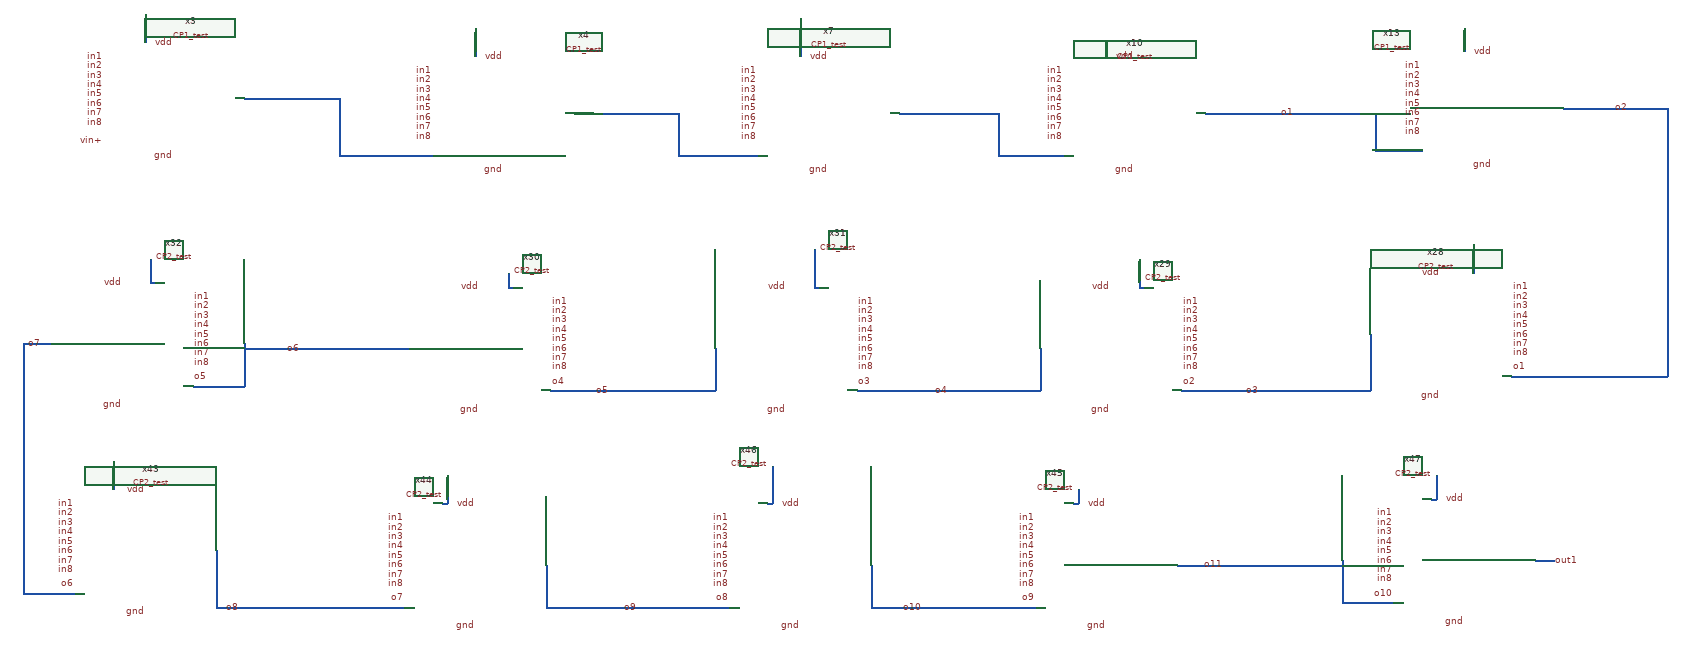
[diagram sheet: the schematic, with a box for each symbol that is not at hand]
v {xschem version=3.4.4 file_version=1.2
}
G {}
K {}
V {}
S {}
E {}
N -1210 -770 -1170 -770 {
lab=#net21}
N -1420 -910 -1420 -890 {
lab=#net22}
N -510 -740 -470 -740 {
lab=#net23}
N -720 -880 -720 -860 {
lab=#net24}
N 180 -740 220 -740 {
lab=#net25}
N -30 -880 -30 -860 {
lab=#net22}
N 830 -740 870 -740 {
lab=o1}
N 620 -880 620 -860 {
lab=#net26}
N 1590 -750 1630 -750 {
lab=o2}
N 1380 -890 1380 -870 {
lab=#net27}
N -1170 -770 -1010 -770 {
lab=#net21}
N -1010 -770 -1010 -650 {
lab=#net21}
N -1010 -650 -810 -650 {
lab=#net21}
N -480 -740 -290 -740 {
lab=#net23}
N -290 -740 -290 -650 {
lab=#net23}
N -290 -650 -120 -650 {
lab=#net23}
N 220 -740 390 -740 {
lab=#net25}
N 390 -740 390 -650 {
lab=#net25}
N 390 -650 530 -650 {
lab=#net25}
N 870 -740 1180 -740 {
lab=o1}
N -1420 -950 -1420 -910 {
lab=#net22}
N -720 -920 -720 -870 {
lab=#net24}
N -30 -940 -30 -880 {
lab=#net22}
N 620 -890 620 -870 {
lab=#net26}
N 1380 -920 1380 -900 {
lab=#net27}
N 1380 -900 1380 -890 {
lab=#net27}
N 690 -390 690 -370 {
lab=#net30}
N 0 -390 0 -370 {
lab=#net32}
N -1660 -250 -1620 -250 {
lab=o7}
N -1410 -400 -1410 -380 {
lab=#net36}
N -1210 -250 -1210 -160 {
lab=o6}
N 690 -430 690 -380 {
lab=#net30}
N 0 -450 0 -390 {
lab=#net32}
N -650 -400 -650 -380 {
lab=#net35}
N -1410 -430 -1410 -410 {
lab=#net36}
N -1410 -410 -1410 -400 {
lab=#net36}
N 1400 -460 1400 -400 {
lab=#net29}
N 690 -370 700 -370 {
lab=#net30}
N 0 -370 10 -370 {
lab=#net32}
N -650 -380 -650 -370 {
lab=#net35}
N -650 -370 -640 -370 {
lab=#net35}
N -1410 -380 -1400 -380 {
lab=#net36}
N -1320 -160 -1210 -160 {
lab=o6}
N -1210 -240 -860 -240 {
lab=o6}
N -560 -150 -210 -150 {
lab=o5}
N -210 -240 -210 -150 {
lab=o5}
N 90 -150 480 -150 {
lab=o4}
N 480 -240 480 -150 {
lab=o4}
N 780 -150 1180 -150 {
lab=o3}
N 1180 -270 1180 -150 {
lab=o3}
N 1480 -180 1570 -180 {
lab=o2}
N -780 70 -780 90 {
lab=#net40}
N -90 70 -90 90 {
lab=#net42}
N 1530 210 1570 210 {
lab=out1}
N 1320 60 1320 80 {
lab=#net46}
N 1120 210 1120 300 {
lab=o11}
N -780 30 -780 80 {
lab=#net40}
N -90 10 -90 70 {
lab=#net42}
N 560 60 560 80 {
lab=#net45}
N 1320 30 1320 50 {
lab=#net46}
N 1320 50 1320 60 {
lab=#net46}
N -1490 0 -1490 60 {
lab=#net39}
N -790 90 -780 90 {
lab=#net40}
N -100 90 -90 90 {
lab=#net42}
N 560 80 560 90 {
lab=#net45}
N 550 90 560 90 {
lab=#net45}
N 1310 80 1320 80 {
lab=#net46}
N 1120 300 1230 300 {
lab=o11}
N 770 220 1120 220 {
lab=o11}
N 120 310 470 310 {
lab=o10}
N 120 220 120 310 {
lab=o10}
N -570 310 -180 310 {
lab=o9}
N -570 220 -570 310 {
lab=o9}
N -1270 310 -870 310 {
lab=o8}
N -1270 190 -1270 310 {
lab=o8}
N 1190 -660 1290 -660 {}
N 1190 -740 1190 -660 {}
N 1160 -740 1190 -740 {}
N 1570 -180 1810 -180 {}
N 1810 -750 1810 -180 {}
N 1630 -750 1810 -750 {}
N -1680 -250 -1660 -250 {}
N -1680 -250 -1680 280 {}
N -1680 280 -1570 280 {}
C {CP1_test.sym} -1360 -770 0 0 {name=x3}
C {devices/lab_pin.sym} -1360 -890 1 0 {name=p143 sig_type=std_logic lab=vdd}
C {devices/lab_pin.sym} -1510 -860 0 0 {name=p145 sig_type=std_logic lab=in1
value=0}
C {devices/lab_pin.sym} -1510 -840 0 0 {name=p146 sig_type=std_logic lab=in2
value=0}
C {devices/lab_pin.sym} -1510 -820 0 0 {name=p147 sig_type=std_logic lab=in3
value=0}
C {devices/lab_pin.sym} -1510 -800 0 0 {name=p148 sig_type=std_logic lab=in4
value=0}
C {devices/lab_pin.sym} -1510 -780 0 0 {name=p149 sig_type=std_logic lab=in5
value=0}
C {devices/lab_pin.sym} -1510 -760 0 0 {name=p150 sig_type=std_logic lab=in6
value=0}
C {devices/lab_pin.sym} -1510 -740 0 0 {name=p151 sig_type=std_logic lab=in7
value=0}
C {devices/lab_pin.sym} -1510 -720 0 0 {name=p152 sig_type=std_logic lab=in8
value=0}
C {devices/lab_pin.sym} -1510 -680 0 0 {name=p153 sig_type=std_logic lab=vin+}
C {devices/lab_pin.sym} -1360 -650 3 0 {name=p190 sig_type=std_logic lab=gnd}
C {CP1_test.sym} -660 -740 0 0 {name=x4}
C {devices/lab_pin.sym} -660 -860 1 0 {name=p157 sig_type=std_logic lab=vdd}
C {devices/lab_pin.sym} -810 -830 0 0 {name=p158 sig_type=std_logic lab=in1
value=0}
C {devices/lab_pin.sym} -810 -810 0 0 {name=p159 sig_type=std_logic lab=in2
value=0}
C {devices/lab_pin.sym} -810 -790 0 0 {name=p160 sig_type=std_logic lab=in3
value=0}
C {devices/lab_pin.sym} -810 -770 0 0 {name=p161 sig_type=std_logic lab=in4
value=0}
C {devices/lab_pin.sym} -810 -750 0 0 {name=p162 sig_type=std_logic lab=in5
value=0}
C {devices/lab_pin.sym} -810 -730 0 0 {name=p163 sig_type=std_logic lab=in6
value=0}
C {devices/lab_pin.sym} -810 -710 0 0 {name=p164 sig_type=std_logic lab=in7
value=0}
C {devices/lab_pin.sym} -810 -690 0 0 {name=p165 sig_type=std_logic lab=in8
value=0}
C {devices/lab_pin.sym} -660 -620 3 0 {name=p166 sig_type=std_logic lab=gnd}
C {CP1_test.sym} 30 -740 0 0 {name=x7}
C {devices/lab_pin.sym} 30 -860 1 0 {name=p172 sig_type=std_logic lab=vdd}
C {devices/lab_pin.sym} -120 -830 0 0 {name=p173 sig_type=std_logic lab=in1
value=0}
C {devices/lab_pin.sym} -120 -810 0 0 {name=p174 sig_type=std_logic lab=in2
value=0}
C {devices/lab_pin.sym} -120 -790 0 0 {name=p175 sig_type=std_logic lab=in3
value=0}
C {devices/lab_pin.sym} -120 -770 0 0 {name=p176 sig_type=std_logic lab=in4
value=0}
C {devices/lab_pin.sym} -120 -750 0 0 {name=p177 sig_type=std_logic lab=in5
value=0}
C {devices/lab_pin.sym} -120 -730 0 0 {name=p178 sig_type=std_logic lab=in6
value=0}
C {devices/lab_pin.sym} -120 -710 0 0 {name=p179 sig_type=std_logic lab=in7
value=0}
C {devices/lab_pin.sym} -120 -690 0 0 {name=p180 sig_type=std_logic lab=in8
value=0}
C {devices/lab_pin.sym} 30 -620 3 0 {name=p181 sig_type=std_logic lab=gnd}
C {CP1_test.sym} 680 -740 0 0 {name=x10}
C {devices/lab_pin.sym} 680 -860 1 0 {name=p186 sig_type=std_logic lab=vdd}
C {devices/lab_pin.sym} 530 -830 0 0 {name=p187 sig_type=std_logic lab=in1
value=0}
C {devices/lab_pin.sym} 530 -810 0 0 {name=p188 sig_type=std_logic lab=in2
value=0}
C {devices/lab_pin.sym} 530 -790 0 0 {name=p189 sig_type=std_logic lab=in3
value=0}
C {devices/lab_pin.sym} 530 -770 0 0 {name=p191 sig_type=std_logic lab=in4
value=0}
C {devices/lab_pin.sym} 530 -750 0 0 {name=p192 sig_type=std_logic lab=in5
value=0}
C {devices/lab_pin.sym} 530 -730 0 0 {name=p193 sig_type=std_logic lab=in6
value=0}
C {devices/lab_pin.sym} 530 -710 0 0 {name=p194 sig_type=std_logic lab=in7
value=0}
C {devices/lab_pin.sym} 530 -690 0 0 {name=p195 sig_type=std_logic lab=in8
value=0}
C {devices/lab_pin.sym} 680 -620 3 0 {name=p196 sig_type=std_logic lab=gnd}
C {CP1_test.sym} 1440 -750 0 0 {name=x13}
C {devices/lab_pin.sym} 1440 -870 1 0 {name=p201 sig_type=std_logic lab=vdd}
C {devices/lab_pin.sym} 1290 -840 0 0 {name=p202 sig_type=std_logic lab=in1
value=0}
C {devices/lab_pin.sym} 1290 -820 0 0 {name=p203 sig_type=std_logic lab=in2
value=0}
C {devices/lab_pin.sym} 1290 -800 0 0 {name=p204 sig_type=std_logic lab=in3
value=0}
C {devices/lab_pin.sym} 1290 -780 0 0 {name=p205 sig_type=std_logic lab=in4
value=0}
C {devices/lab_pin.sym} 1290 -760 0 0 {name=p206 sig_type=std_logic lab=in5
value=0}
C {devices/lab_pin.sym} 1290 -740 0 0 {name=p207 sig_type=std_logic lab=in6
value=0}
C {devices/lab_pin.sym} 1290 -720 0 0 {name=p208 sig_type=std_logic lab=in7
value=0}
C {devices/lab_pin.sym} 1290 -700 0 0 {name=p209 sig_type=std_logic lab=in8
value=0}
C {devices/lab_pin.sym} 1440 -630 3 0 {name=p210 sig_type=std_logic lab=gnd}
C {devices/lab_pin.sym} 1330 -400 3 1 {name=p216 sig_type=std_logic lab=vdd}
C {devices/lab_pin.sym} 1480 -370 0 1 {name=p218 sig_type=std_logic lab=in1
value=0}
C {devices/lab_pin.sym} 1480 -350 0 1 {name=p219 sig_type=std_logic lab=in2
value=0}
C {devices/lab_pin.sym} 1480 -330 0 1 {name=p220 sig_type=std_logic lab=in3
value=0}
C {devices/lab_pin.sym} 1480 -310 0 1 {name=p221 sig_type=std_logic lab=in4
value=0}
C {devices/lab_pin.sym} 1480 -290 0 1 {name=p222 sig_type=std_logic lab=in5
value=0}
C {devices/lab_pin.sym} 1480 -270 0 1 {name=p223 sig_type=std_logic lab=in6
value=0}
C {devices/lab_pin.sym} 1480 -250 0 1 {name=p224 sig_type=std_logic lab=in7
value=0}
C {devices/lab_pin.sym} 1480 -230 0 1 {name=p225 sig_type=std_logic lab=in8
value=0}
C {devices/lab_pin.sym} 1330 -140 1 1 {name=p227 sig_type=std_logic lab=gnd}
C {devices/lab_pin.sym} 630 -370 3 1 {name=p232 sig_type=std_logic lab=vdd}
C {devices/lab_pin.sym} 780 -340 0 1 {name=p233 sig_type=std_logic lab=in1
value=0}
C {devices/lab_pin.sym} 780 -320 0 1 {name=p234 sig_type=std_logic lab=in2
value=0}
C {devices/lab_pin.sym} 780 -300 0 1 {name=p235 sig_type=std_logic lab=in3
value=0}
C {devices/lab_pin.sym} 780 -280 0 1 {name=p236 sig_type=std_logic lab=in4
value=0}
C {devices/lab_pin.sym} 780 -260 0 1 {name=p237 sig_type=std_logic lab=in5
value=0}
C {devices/lab_pin.sym} 780 -240 0 1 {name=p238 sig_type=std_logic lab=in6
value=0}
C {devices/lab_pin.sym} 780 -220 0 1 {name=p239 sig_type=std_logic lab=in7
value=0}
C {devices/lab_pin.sym} 780 -200 0 1 {name=p240 sig_type=std_logic lab=in8
value=0}
C {devices/lab_pin.sym} 630 -110 1 1 {name=p241 sig_type=std_logic lab=gnd}
C {devices/lab_pin.sym} -60 -370 3 1 {name=p246 sig_type=std_logic lab=vdd}
C {devices/lab_pin.sym} 90 -340 0 1 {name=p247 sig_type=std_logic lab=in1
value=0}
C {devices/lab_pin.sym} 90 -320 0 1 {name=p248 sig_type=std_logic lab=in2
value=0}
C {devices/lab_pin.sym} 90 -300 0 1 {name=p249 sig_type=std_logic lab=in3
value=0}
C {devices/lab_pin.sym} 90 -280 0 1 {name=p250 sig_type=std_logic lab=in4
value=0}
C {devices/lab_pin.sym} 90 -260 0 1 {name=p251 sig_type=std_logic lab=in5
value=0}
C {devices/lab_pin.sym} 90 -240 0 1 {name=p252 sig_type=std_logic lab=in6
value=0}
C {devices/lab_pin.sym} 90 -220 0 1 {name=p253 sig_type=std_logic lab=in7
value=0}
C {devices/lab_pin.sym} 90 -200 0 1 {name=p254 sig_type=std_logic lab=in8
value=0}
C {devices/lab_pin.sym} -60 -110 1 1 {name=p255 sig_type=std_logic lab=gnd}
C {devices/lab_pin.sym} -710 -370 3 1 {name=p260 sig_type=std_logic lab=vdd}
C {devices/lab_pin.sym} -560 -340 0 1 {name=p261 sig_type=std_logic lab=in1
value=0}
C {devices/lab_pin.sym} -560 -320 0 1 {name=p262 sig_type=std_logic lab=in2
value=0}
C {devices/lab_pin.sym} -560 -300 0 1 {name=p263 sig_type=std_logic lab=in3
value=0}
C {devices/lab_pin.sym} -560 -280 0 1 {name=p264 sig_type=std_logic lab=in4
value=0}
C {devices/lab_pin.sym} -560 -260 0 1 {name=p265 sig_type=std_logic lab=in5
value=0}
C {devices/lab_pin.sym} -560 -240 0 1 {name=p266 sig_type=std_logic lab=in6
value=0}
C {devices/lab_pin.sym} -560 -220 0 1 {name=p267 sig_type=std_logic lab=in7
value=0}
C {devices/lab_pin.sym} -560 -200 0 1 {name=p268 sig_type=std_logic lab=in8
value=0}
C {devices/lab_pin.sym} -710 -110 1 1 {name=p269 sig_type=std_logic lab=gnd}
C {devices/lab_pin.sym} -1470 -380 3 1 {name=p274 sig_type=std_logic lab=vdd}
C {devices/lab_pin.sym} -1320 -350 0 1 {name=p275 sig_type=std_logic lab=in1
value=0}
C {devices/lab_pin.sym} -1320 -330 0 1 {name=p276 sig_type=std_logic lab=in2
value=0}
C {devices/lab_pin.sym} -1320 -310 0 1 {name=p277 sig_type=std_logic lab=in3
value=0}
C {devices/lab_pin.sym} -1320 -290 0 1 {name=p278 sig_type=std_logic lab=in4
value=0}
C {devices/lab_pin.sym} -1320 -270 0 1 {name=p279 sig_type=std_logic lab=in5
value=0}
C {devices/lab_pin.sym} -1320 -250 0 1 {name=p280 sig_type=std_logic lab=in6
value=0}
C {devices/lab_pin.sym} -1320 -230 0 1 {name=p281 sig_type=std_logic lab=in7
value=0}
C {devices/lab_pin.sym} -1320 -210 0 1 {name=p282 sig_type=std_logic lab=in8
value=0}
C {devices/lab_pin.sym} -1470 -120 1 1 {name=p283 sig_type=std_logic lab=gnd}
C {CP2_test.sym} 1330 -270 0 1 {name=x28}
C {CP2_test.sym} 630 -240 0 1 {name=x29}
C {CP2_test.sym} -710 -240 0 1 {name=x30}
C {CP2_test.sym} -60 -240 0 1 {name=x31}
C {CP2_test.sym} -1470 -250 0 1 {name=x32}
C {devices/lab_pin.sym} -1420 60 1 0 {name=p215 sig_type=std_logic lab=vdd}
C {devices/lab_pin.sym} -1570 90 0 0 {name=p290 sig_type=std_logic lab=in1
value=0}
C {devices/lab_pin.sym} -1570 110 0 0 {name=p291 sig_type=std_logic lab=in2
value=0}
C {devices/lab_pin.sym} -1570 130 0 0 {name=p292 sig_type=std_logic lab=in3
value=0}
C {devices/lab_pin.sym} -1570 150 0 0 {name=p293 sig_type=std_logic lab=in4
value=0}
C {devices/lab_pin.sym} -1570 170 0 0 {name=p294 sig_type=std_logic lab=in5
value=0}
C {devices/lab_pin.sym} -1570 190 0 0 {name=p295 sig_type=std_logic lab=in6
value=0}
C {devices/lab_pin.sym} -1570 210 0 0 {name=p296 sig_type=std_logic lab=in7
value=0}
C {devices/lab_pin.sym} -1570 230 0 0 {name=p297 sig_type=std_logic lab=in8
value=0}
C {devices/lab_pin.sym} -1420 320 3 0 {name=p299 sig_type=std_logic lab=gnd}
C {devices/lab_pin.sym} -720 90 1 0 {name=p304 sig_type=std_logic lab=vdd}
C {devices/lab_pin.sym} -870 120 0 0 {name=p305 sig_type=std_logic lab=in1
value=0}
C {devices/lab_pin.sym} -870 140 0 0 {name=p306 sig_type=std_logic lab=in2
value=0}
C {devices/lab_pin.sym} -870 160 0 0 {name=p307 sig_type=std_logic lab=in3
value=0}
C {devices/lab_pin.sym} -870 180 0 0 {name=p308 sig_type=std_logic lab=in4
value=0}
C {devices/lab_pin.sym} -870 200 0 0 {name=p309 sig_type=std_logic lab=in5
value=0}
C {devices/lab_pin.sym} -870 220 0 0 {name=p310 sig_type=std_logic lab=in6
value=0}
C {devices/lab_pin.sym} -870 240 0 0 {name=p311 sig_type=std_logic lab=in7
value=0}
C {devices/lab_pin.sym} -870 260 0 0 {name=p312 sig_type=std_logic lab=in8
value=0}
C {devices/lab_pin.sym} -720 350 3 0 {name=p313 sig_type=std_logic lab=gnd}
C {devices/lab_pin.sym} -30 90 1 0 {name=p318 sig_type=std_logic lab=vdd}
C {devices/lab_pin.sym} -180 120 0 0 {name=p319 sig_type=std_logic lab=in1
value=0}
C {devices/lab_pin.sym} -180 140 0 0 {name=p320 sig_type=std_logic lab=in2
value=0}
C {devices/lab_pin.sym} -180 160 0 0 {name=p321 sig_type=std_logic lab=in3
value=0}
C {devices/lab_pin.sym} -180 180 0 0 {name=p322 sig_type=std_logic lab=in4
value=0}
C {devices/lab_pin.sym} -180 200 0 0 {name=p323 sig_type=std_logic lab=in5
value=0}
C {devices/lab_pin.sym} -180 220 0 0 {name=p324 sig_type=std_logic lab=in6
value=0}
C {devices/lab_pin.sym} -180 240 0 0 {name=p325 sig_type=std_logic lab=in7
value=0}
C {devices/lab_pin.sym} -180 260 0 0 {name=p326 sig_type=std_logic lab=in8
value=0}
C {devices/lab_pin.sym} -30 350 3 0 {name=p327 sig_type=std_logic lab=gnd}
C {devices/lab_pin.sym} 620 90 1 0 {name=p332 sig_type=std_logic lab=vdd}
C {devices/lab_pin.sym} 470 120 0 0 {name=p333 sig_type=std_logic lab=in1
value=0}
C {devices/lab_pin.sym} 470 140 0 0 {name=p334 sig_type=std_logic lab=in2
value=0}
C {devices/lab_pin.sym} 470 160 0 0 {name=p335 sig_type=std_logic lab=in3
value=0}
C {devices/lab_pin.sym} 470 180 0 0 {name=p336 sig_type=std_logic lab=in4
value=0}
C {devices/lab_pin.sym} 470 200 0 0 {name=p337 sig_type=std_logic lab=in5
value=0}
C {devices/lab_pin.sym} 470 220 0 0 {name=p338 sig_type=std_logic lab=in6
value=0}
C {devices/lab_pin.sym} 470 240 0 0 {name=p339 sig_type=std_logic lab=in7
value=0}
C {devices/lab_pin.sym} 470 260 0 0 {name=p340 sig_type=std_logic lab=in8
value=0}
C {devices/lab_pin.sym} 620 350 3 0 {name=p341 sig_type=std_logic lab=gnd}
C {devices/lab_pin.sym} 1380 80 1 0 {name=p346 sig_type=std_logic lab=vdd}
C {devices/lab_pin.sym} 1230 110 0 0 {name=p347 sig_type=std_logic lab=in1
value=0}
C {devices/lab_pin.sym} 1230 130 0 0 {name=p348 sig_type=std_logic lab=in2
value=0}
C {devices/lab_pin.sym} 1230 150 0 0 {name=p349 sig_type=std_logic lab=in3
value=0}
C {devices/lab_pin.sym} 1230 170 0 0 {name=p350 sig_type=std_logic lab=in4
value=0}
C {devices/lab_pin.sym} 1230 190 0 0 {name=p351 sig_type=std_logic lab=in5
value=0}
C {devices/lab_pin.sym} 1230 210 0 0 {name=p352 sig_type=std_logic lab=in6
value=0}
C {devices/lab_pin.sym} 1230 230 0 0 {name=p353 sig_type=std_logic lab=in7
value=0}
C {devices/lab_pin.sym} 1230 250 0 0 {name=p354 sig_type=std_logic lab=in8
value=0}
C {devices/lab_pin.sym} 1380 340 3 0 {name=p355 sig_type=std_logic lab=gnd}
C {devices/lab_pin.sym} 1570 210 2 0 {name=p361 sig_type=std_logic lab=out1}
C {CP2_test.sym} -1420 190 0 0 {name=x43}
C {CP2_test.sym} -720 220 0 0 {name=x44}
C {CP2_test.sym} 620 220 0 0 {name=x45}
C {CP2_test.sym} -30 220 0 0 {name=x46}
C {CP2_test.sym} 1380 210 0 0 {name=x47}
C {devices/lab_pin.sym} 1020 -740 3 0 {name=p630 sig_type=std_logic lab=o1}
C {devices/lab_pin.sym} 1730 -750 3 0 {name=p631 sig_type=std_logic lab=o2}
C {devices/lab_pin.sym} 1480 -200 2 0 {name=p632 sig_type=std_logic lab=o1}
C {devices/lab_pin.sym} 780 -170 2 0 {name=p633 sig_type=std_logic lab=o2}
C {devices/lab_pin.sym} 945 -150 3 0 {name=p634 sig_type=std_logic lab=o3}
C {devices/lab_pin.sym} 285 -150 3 0 {name=p635 sig_type=std_logic lab=o4}
C {devices/lab_pin.sym} 90 -170 2 0 {name=p636 sig_type=std_logic lab=o3}
C {devices/lab_pin.sym} -560 -170 2 0 {name=p637 sig_type=std_logic lab=o4}
C {devices/lab_pin.sym} -435 -150 3 0 {name=p638 sig_type=std_logic lab=o5}
C {devices/lab_pin.sym} -1090 -240 3 0 {name=p639 sig_type=std_logic lab=o6}
C {devices/lab_pin.sym} -1320 -180 2 0 {name=p640 sig_type=std_logic lab=o5}
C {devices/lab_pin.sym} -1640 -250 3 0 {name=p641 sig_type=std_logic lab=o7}
C {devices/lab_pin.sym} -1220 310 3 0 {name=p642 sig_type=std_logic lab=o8}
C {devices/lab_pin.sym} -1570 260 0 0 {name=p643 sig_type=std_logic lab=o6}
C {devices/lab_pin.sym} -870 290 0 0 {name=p644 sig_type=std_logic lab=o7}
C {devices/lab_pin.sym} -375 310 3 0 {name=p645 sig_type=std_logic lab=o9}
C {devices/lab_pin.sym} -180 290 0 0 {name=p646 sig_type=std_logic lab=o8}
C {devices/lab_pin.sym} 230 310 3 0 {name=p647 sig_type=std_logic lab=o10}
C {devices/lab_pin.sym} 470 290 0 0 {name=p648 sig_type=std_logic lab=o9}
C {devices/lab_pin.sym} 1230 280 0 0 {name=p649 sig_type=std_logic lab=o10}
C {devices/lab_pin.sym} 870 220 3 0 {name=p650 sig_type=std_logic lab=o11}
